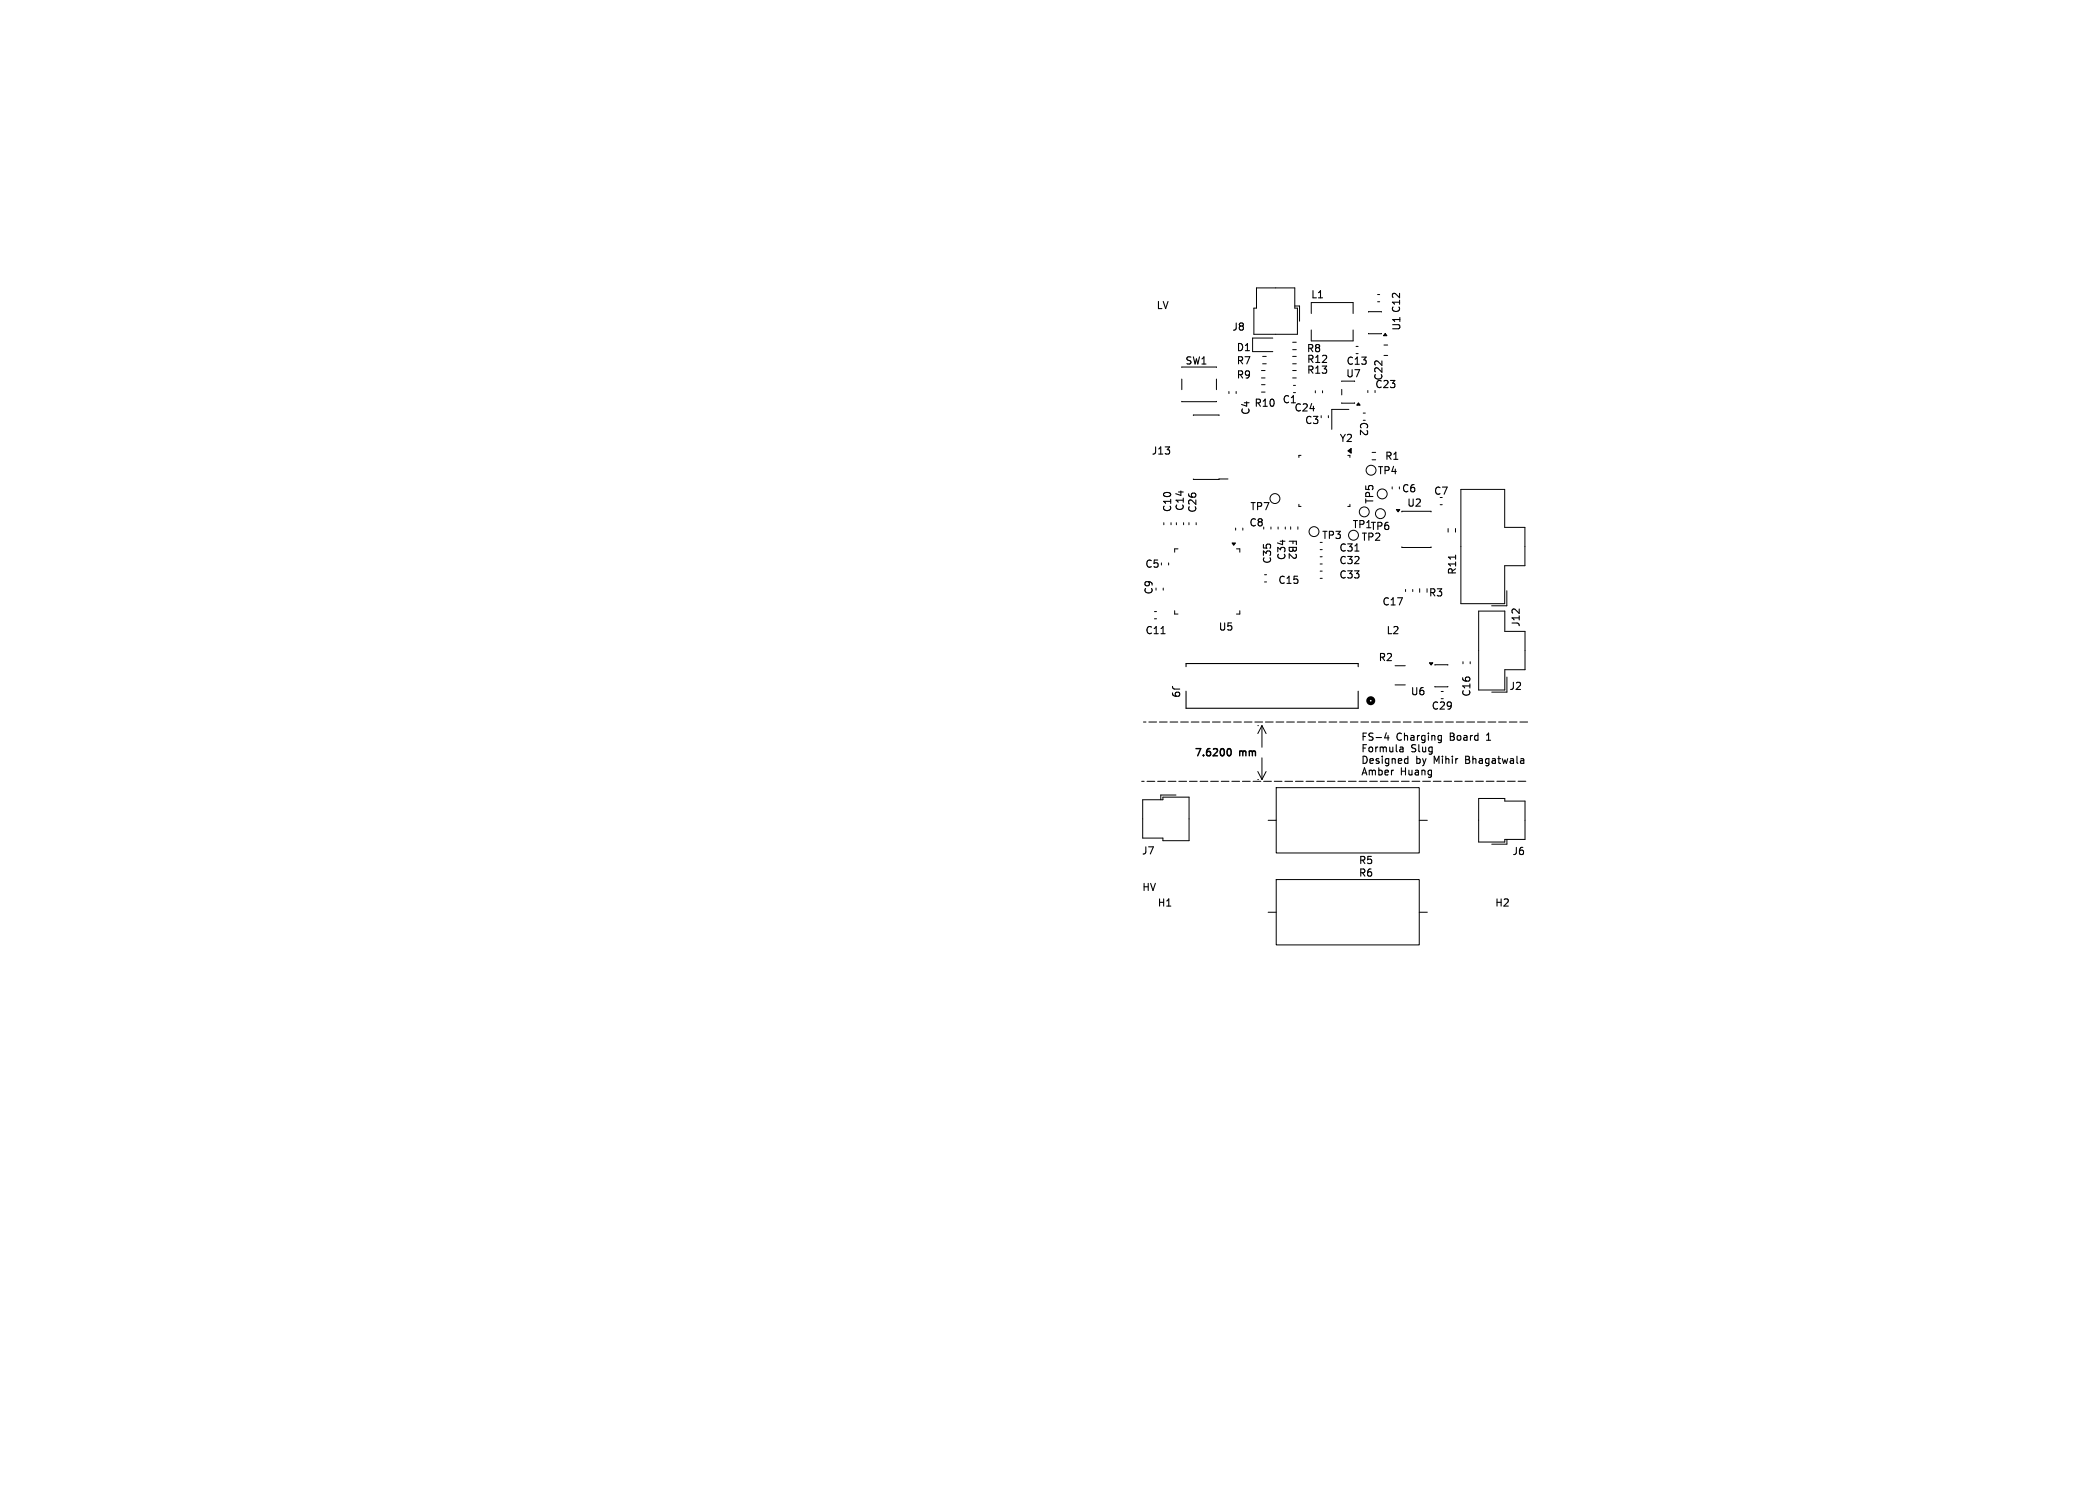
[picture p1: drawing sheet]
<svg xmlns="http://www.w3.org/2000/svg" width="297mm" height="210mm" viewBox="0 0 297 210" stroke-linecap="round" stroke-linejoin="round" font-family="sans-serif">
<defs><g id="words">
<g font-size="1.4">
<text x="163.6" y="43.9">LV</text>
<text x="174.3" y="47">J8</text>
<text x="185.4" y="42.4">L1</text>
<text x="198.3" y="46.9" transform="rotate(-90 198.3 46.9)">U1 C12</text>
<text x="167.6" y="51.8">SW1</text>
<text x="174.9" y="49.9">D1</text>
<text x="174.9" y="53.7">R9</text>
<text x="174.9" y="51.7">R7</text>
<text x="184.8" y="50">R8</text>
<text x="184.8" y="53.1">R13</text>
<text x="184.8" y="51.5">R12</text>
<text x="190.4" y="53.6">U7</text>
<text x="190.4" y="51.8">C13</text>
<text x="195.8" y="53.9" transform="rotate(-90 195.8 53.9)">C22</text>
<text x="177" y="58.8" transform="rotate(-90 177 58.8)">C4</text>
<text x="177.4" y="57.7">R10</text>
<text x="181.4" y="57.2">C1</text>
<text x="183.1" y="58.4">C24</text>
<text x="192.2" y="59.6" transform="rotate(90 192.2 59.6)">C2</text>
<text x="194.5" y="55.1">C23</text>
<text x="162.9" y="64.5">J13</text>
<text x="184.6" y="60.2">C3</text>
<text x="189.5" y="62.7">Y2</text>
<text x="195.9" y="65.2">R1</text>
<text x="194.5" y="71.4" transform="rotate(-90 194.5 71.4)">TP5</text>
<text x="194.8" y="67.3">TP4</text>
<text x="198.3" y="69.8">C6</text>
<text x="199" y="71.9">U2</text>
<text x="202.8" y="70.2">C7</text>
<text x="165.9" y="72.5" transform="rotate(-90 165.9 72.5)">C10</text>
<text x="167.7" y="72.4" transform="rotate(-90 167.7 72.4)">C14</text>
<text x="169.5" y="72.6" transform="rotate(-90 169.5 72.6)">C26</text>
<text x="176.7" y="74.7">C8</text>
<text x="176.8" y="72.4">TP7</text>
<text x="182.1" y="76.2" transform="rotate(90 182.1 76.2)">FB2</text>
<text x="187" y="76.4">TP3</text>
<text x="191.3" y="74.9">TP1TP6</text>
<text x="192.6" y="76.7">TP2</text>
<text x="161.9" y="80.5">C5</text>
<text x="180.1" y="79.8" transform="rotate(-90 180.1 79.8)">C35</text>
<text x="180.8" y="82.8">C15</text>
<text x="182.1" y="79.3" transform="rotate(-90 182.1 79.3)">C34</text>
<text x="189.4" y="82">C33</text>
<text x="189.4" y="80">C32</text>
<text x="189.4" y="78.2">C31</text>
<text x="206.2" y="81.4" transform="rotate(-90 206.2 81.4)">R11</text>
<text x="162" y="89.9">C11</text>
<text x="163.3" y="84.2" transform="rotate(-90 163.3 84.2)">C9</text>
<text x="172.3" y="89.4">U5</text>
<text x="195.5" y="85.8">C17</text>
<text x="196.1" y="89.9">L2</text>
<text x="202.1" y="84.6">R3</text>
<text x="215.2" y="88.8" transform="rotate(-90 215.2 88.8)">J12</text>
<text x="195" y="93.7">R2</text>
<text x="165.6" y="96.8" transform="rotate(90 165.6 96.8)">J9</text>
<text x="199.5" y="98.5">U6</text>
<text x="202.5" y="100.6">C29</text>
<text x="208.3" y="98.6" transform="rotate(-90 208.3 98.6)">C16</text>
<text x="213.5" y="97.8">J2</text>
<text x="168.9" y="107.2">7.6200</text>
<text x="175.4" y="107.2">mm</text>
<text x="192.5" y="105">FS-4</text>
<text x="192.5" y="106.6">Formula</text>
<text x="197.6" y="105">Charging</text>
<text x="199.7" y="106.6">Slug</text>
<text x="205.4" y="105">Board</text>
<text x="210.8" y="105">1</text>
<text x="192.5" y="108.2">Designed</text>
<text x="192.5" y="109.9">Amber</text>
<text x="198.2" y="109.9">Huang</text>
<text x="200.4" y="108.2">by</text>
<text x="203.1" y="108.2">Mihir</text>
<text x="207.8" y="108.2">Bhagatwala</text>
<text x="161.5" y="121">J7</text>
<text x="192.2" y="124.2">R6</text>
<text x="192.2" y="122.4">R5</text>
<text x="213.9" y="121.1">J6</text>
<text x="161.5" y="126.2">HV</text>
<text x="163.7" y="128.4">H1</text>
<text x="211.5" y="128.4">H2</text>
</g>
</g></defs>
<g fill="none" stroke="#000" stroke-width=".14">
<path d="M167.2 53.6v1.5M167.2 56.8h4.9M167.2 51.9l4.9 .1M168.9 58.8h3.6M172.1 53.6v1.5M173.9 55.4v.3M174.9 55.4v.3M177.8 40.7h5.4v2.9h.4v3.7h-6.2v-3.7h.4zM178.5 52.4h.5M178.5 53.4h.5M178.5 54.4h.5M178.5 55.4h.5"/>
<path d="M178.7 50.4h.5M178.7 51.4h.5M180.1 47.8h-2.9v1.9h2.9M182.9 52.4h.5M182.9 53.4h.5M182.9 50.4h.5M182.9 51.4h.5M182.9 48.4h.5M182.9 49.4h.5M183 54.5h.3M183 55.5h.3M183.2 43.3h.7v2.1"/>
<path d="M185.5 44.3v-1.5h6v1.5M185.5 46.7v1.5h6v-1.5M186.1 55.3v.3M186.9 58.8v.3M187.1 55.3v.3M188 58.8v.3M189.9 55.1v.7M189.9 57h1.8M190.9 57.9h-2.5v2.8M191.7 53.9h-1.8M191.9 49h.3M191.9 50h.3"/>
<path d="M192.9 58.4h.3M193.5 55.2v.3M193.6 44.1h1.9M193.6 47.1h1.9M194.9 41.7h.3M194.9 42.7h.3M195.8 48.8h.5M195.8 50.3h.5M164.3 79.6v.3M164.7 73.9v.3M165.4 79.6v.3M165.7 73.9v.3"/>
<path d="M166.5 73.9v.3M166.7 77.6h-.5v.5M167.5 73.9v.3M168.2 73.9v.3M168.9 67.7h4.9M169.3 73.9v.3M174.8 74.7v.3M175 77.6h.4v.5M175.9 74.7v.3M179.8 74.5v.3M180.8 74.5v.3M181.9 74.5v.3"/>
<path d="M182.6 74.5v.3M183.6 74.5v.3M183.8 71.3v.3h.3M184.1 64.4h-.3v.3M186.8 78.7h.3M186.8 79.8h.3M186.8 77.7h.3M190.7 64.4h.3v.3M191 71.3v.3h-.3M194.1 64h.6M194.1 65h.6M197 68.9v.2"/>
<path d="M198.4 72.4v-.1h4.1v.1M198.4 77.3v.1h4.1v-.1M203.8 71.4h.3M204.9 74.7v.6M205.9 74.7v.6M206.7 69.2h6.2v5.4h2.9v5.4h-2.9v5.4h-6.2zM163.4 86.5h.2M163.4 87.5h.2M164.6 83.2v.3M166.2 86.4v.4h.5M175.4 86.4v.4h-.4M178.9 81.3h.3"/>
<path d="M178.9 82.3h.3M186.8 80.8h.3M186.8 81.8h.3M197.4 94.1h1.4M197.4 96.9h1.4M198.9 83.4v.3M199.9 83.4v.3M200.9 83.3v.5M203 94.1h1.9M203 97.1h1.9M203.9 97.8h.3M203.9 98.8h.3"/>
<path d="M207 93.6v.3M208 93.6v.3M209.2 86.4h3.7v2.9h2.9v5.4h-2.9v2.9h-3.7zM213.2 83.5v2.2h-2.1M213.2 95.8v2.1h-2.1M161.7 113.1h2.8v-.4h3.7v6.2h-3.7v-.4h-2.8zM161.8 102.1h.4M161.9 110.5h-.4M162.6 102.1h1.1M163.4 110.5h-1.1M164.1 102.1h1.1M164.9 110.5h-1.1"/>
<path d="M165.6 102.1h1.1M166.4 112.4h-2.2v.7M166.4 110.5h-1.1M167.1 102.1h1.1M167.9 110.5h-1.1M168.6 102.1h1.1M169.4 110.5h-1.1M170.1 102.1h1.1M170.9 110.5h-1.1M171.6 102.1h1.1M172.4 110.5h-1.1M173.1 102.1h1.1"/>
<path d="M173.9 110.5h-1.1M174.6 102.1h1.1M175.4 110.5h-1.1M176.1 102.1h1.1M176.9 110.5h-1.1M177.6 102.1h1.1M178 110.2h.1M178 102.6h.1M178 109.1l.6 1.1M178.4 110.5h-1.1M178.6 102.6v3.1M178.6 107.2v3"/>
<path d="M178.6 102.6l.5 1.1M178.6 102.6l-.6 1.1M179.1 102.1h1.1M179.1 109.1l-.5 1.1M179.4 116h1.2M179.9 110.5h-1.1M180.6 102.1h1.1M180.6 111.4h20.2v9.2h-20.2zM181.4 110.5h-1.1M182.1 102.1h1.1M182.9 110.5h-1.1M183.6 102.1h1.1"/>
<path d="M184.4 110.5h-1.1M185.1 102.1h1.1M185.9 110.5h-1.1M186.6 102.1h1.1M187.4 110.5h-1.1M188.1 102.1h1.1M188.9 110.5h-1.1M189.6 102.1h1.1M190.4 110.5h-1.1M191.1 102.1h1.1M191.9 110.5h-1.1M192.6 102.1h1.1"/>
<path d="M193.4 110.5h-1.1M194.1 102.1h1.1M194.9 110.5h-1.1M195.6 102.1h1.1M196.4 110.5h-1.1M197.1 102.1h1.1M197.9 110.5h-1.1M198.6 102.1h1.1M200.1 102.1h1.1M200.8 116h1.2M201.6 102.1h1.1M203.1 102.1h1.1"/>
<path d="M203.9 110.5h-1.1M204.6 102.1h1.1M205.4 110.5h-1.1M206.1 102.1h1.1M206.9 110.5h-1.1M207.6 102.1h1.1M208.4 110.5h-1.1M209.1 102.1h1.1M209.2 112.9h3.7v.4h2.9v5.4h-2.9v.4h-3.7zM209.9 110.5h-1.1M210.6 102.1h1.1M211.4 110.5h-1.1"/>
<path d="M212.1 102.1h1.1M212.9 110.5h-1.1M213.2 118.7v.7h-2.1M213.6 102.1h1.1M214.4 110.5h-1.1M215.1 102.1h1.1M215.9 110.5h-1.1M179.4 129h1.2M180.6 124.4h20.2v9.2h-20.2zM200.8 129h1.2"/>
<circle cx="180.4" cy="70.5" r=".7"/>
<circle cx="185.9" cy="75.2" r=".7"/>
<circle cx="191.5" cy="75.7" r=".7"/>
<circle cx="193" cy="72.4" r=".7"/>
<circle cx="194" cy="66.5" r=".7"/>
<circle cx="195.3" cy="72.6" r=".7"/>
<circle cx="195.6" cy="69.8" r=".7"/>
</g>
<g fill="none" stroke="#000" stroke-width=".15">
<path d="M191.7 77.9h.6M206 78.5v.6M164.3 89.6h.6M167.8 94.3v-.5h24.4v.5M167.8 97.7v2.5h24.4v-2.5M196.2 103.6l-.3 .7h.7M196.4 104v.7M198.1 106.3h.4M198.5 105.7v.6M198.5 105.9l-.4 .1M198.9 107.3h.3M199.2 106.9v1.1"/>
<path d="M199.2 107.9l-.3 .1M203.7 104l.3 .1M204 104v.8l-.2 .2M204 104.6l-.3 .1M207.4 107.4h.3M207.7 106.9h-.3v1.1h.4M210.3 104.7h.6M210.5 103.8l-.2 .2"/>
</g>
<path d="M173.6 106.3l.1-.3 .2-.1a.54 .54 0 0 1 .3 .5 .54 .54 0 0 1-.3 .5l-.2-.1-.1-.3" fill="none" stroke="#000" stroke-width=".2"/>
<path d="M192.2 57l.3 .3h-.5zM196 47.1l.2 .4h-.4zM174.3 76.8h.5l-.2 .3zM190.7 63.8l.5-.4v.7zM197.6 72.1h.5l-.3 .3zM202.3 93.7h.4l-.2 .4z" fill="#000" stroke="#000" stroke-width=".14"/>
<circle cx="194" cy="99.1" r=".38" fill="none" stroke="#000" stroke-width=".51"/>
<use href="#words"/>
</svg>
